VERSION 5.7 ;
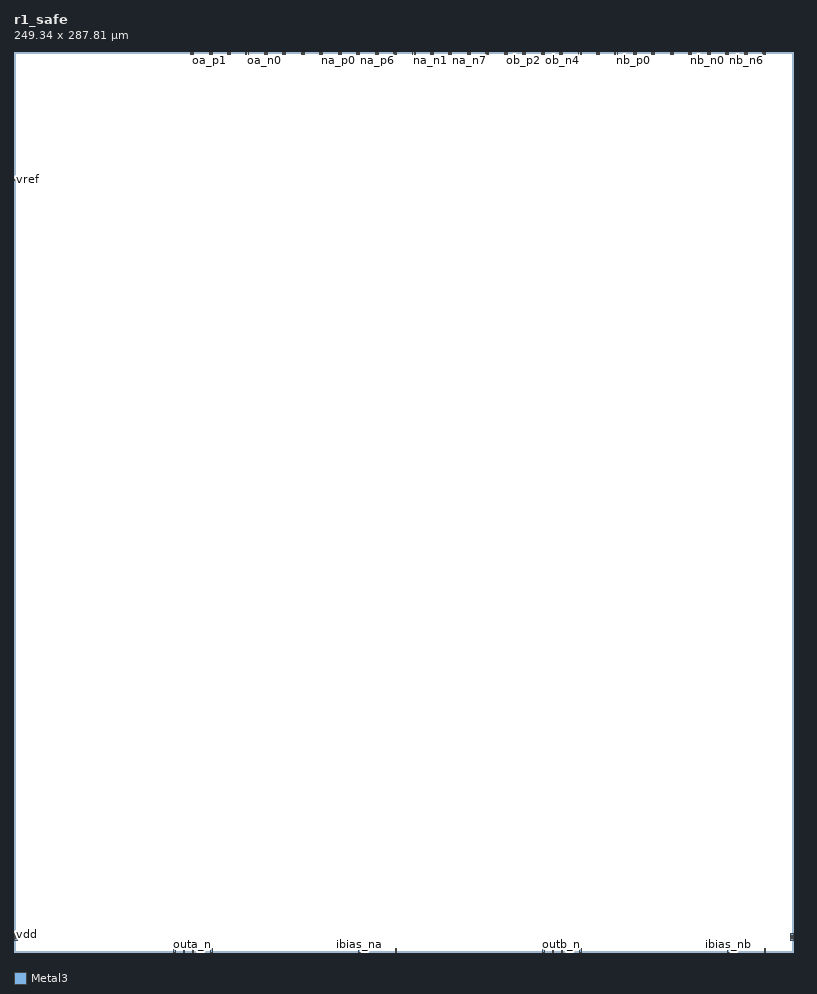
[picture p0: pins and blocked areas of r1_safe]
MACRO r1_safe
  CLASS BLOCK ;
  ORIGIN 0 0 ;
  SIZE 249.340 BY 287.810 ;
  PIN vref
    DIRECTION INOUT ;
    PORT
      LAYER Metal3 ;
        RECT 0.000 246.830 1.000 247.070 ;
    END
  END vref
  PIN vss
    DIRECTION INOUT ; USE GROUND ;
    PORT
      LAYER Metal3 ;
        RECT 0.000 3.800 1.000 4.200 ;
      LAYER Metal3 ;
        RECT 248.340 3.800 249.340 4.200 ;
    END
  END vss
  PIN vdda
    DIRECTION INOUT ; USE POWER ;
    PORT
      LAYER Metal3 ;
        RECT 0.000 4.600 1.000 5.000 ;
      LAYER Metal3 ;
        RECT 248.340 4.600 249.340 5.000 ;
    END
  END vdda
  PIN vdd
    DIRECTION INOUT ; USE POWER ;
    PORT
      LAYER Metal3 ;
        RECT 0.000 5.400 1.000 5.800 ;
      LAYER Metal3 ;
        RECT 248.340 5.400 249.340 5.800 ;
    END
  END vdd
  PIN oa_p0
    DIRECTION INOUT ;
    PORT
      LAYER Metal3 ;
        RECT 56.480 286.860 56.780 287.810 ;
    END
  END oa_p0
  PIN oa_p1
    DIRECTION INOUT ;
    PORT
      LAYER Metal3 ;
        RECT 62.380 286.860 62.680 287.810 ;
    END
  END oa_p1
  PIN oa_p2
    DIRECTION INOUT ;
    PORT
      LAYER Metal3 ;
        RECT 68.280 286.860 68.580 287.810 ;
    END
  END oa_p2
  PIN oa_p3
    DIRECTION INOUT ;
    PORT
      LAYER Metal3 ;
        RECT 74.180 286.860 74.480 287.810 ;
    END
  END oa_p3
  PIN oa_p4
    DIRECTION INOUT ;
    PORT
      LAYER Metal3 ;
        RECT 57.145 286.860 57.445 287.810 ;
    END
  END oa_p4
  PIN oa_p5
    DIRECTION INOUT ;
    PORT
      LAYER Metal3 ;
        RECT 63.045 286.860 63.345 287.810 ;
    END
  END oa_p5
  PIN oa_p6
    DIRECTION INOUT ;
    PORT
      LAYER Metal3 ;
        RECT 68.945 286.860 69.245 287.810 ;
    END
  END oa_p6
  PIN oa_p7
    DIRECTION INOUT ;
    PORT
      LAYER Metal3 ;
        RECT 74.845 286.860 75.145 287.810 ;
    END
  END oa_p7
  PIN oa_n0
    DIRECTION INOUT ;
    PORT
      LAYER Metal3 ;
        RECT 80.080 286.860 80.380 287.810 ;
    END
  END oa_n0
  PIN oa_n1
    DIRECTION INOUT ;
    PORT
      LAYER Metal3 ;
        RECT 85.980 286.860 86.280 287.810 ;
    END
  END oa_n1
  PIN oa_n2
    DIRECTION INOUT ;
    PORT
      LAYER Metal3 ;
        RECT 91.880 286.860 92.180 287.810 ;
    END
  END oa_n2
  PIN oa_n3
    DIRECTION INOUT ;
    PORT
      LAYER Metal3 ;
        RECT 97.780 286.860 98.080 287.810 ;
    END
  END oa_n3
  PIN oa_n4
    DIRECTION INOUT ;
    PORT
      LAYER Metal3 ;
        RECT 80.745 286.860 81.045 287.810 ;
    END
  END oa_n4
  PIN oa_n5
    DIRECTION INOUT ;
    PORT
      LAYER Metal3 ;
        RECT 86.645 286.860 86.945 287.810 ;
    END
  END oa_n5
  PIN oa_n6
    DIRECTION INOUT ;
    PORT
      LAYER Metal3 ;
        RECT 92.545 286.860 92.845 287.810 ;
    END
  END oa_n6
  PIN oa_n7
    DIRECTION INOUT ;
    PORT
      LAYER Metal3 ;
        RECT 98.445 286.860 98.745 287.810 ;
    END
  END oa_n7
  PIN na_p0
    DIRECTION INOUT ;
    PORT
      LAYER Metal3 ;
        RECT 103.680 286.860 103.980 287.810 ;
    END
  END na_p0
  PIN na_p1
    DIRECTION INOUT ;
    PORT
      LAYER Metal3 ;
        RECT 109.580 286.860 109.880 287.810 ;
    END
  END na_p1
  PIN na_p2
    DIRECTION INOUT ;
    PORT
      LAYER Metal3 ;
        RECT 115.480 286.860 115.780 287.810 ;
    END
  END na_p2
  PIN na_p3
    DIRECTION INOUT ;
    PORT
      LAYER Metal3 ;
        RECT 121.380 286.860 121.680 287.810 ;
    END
  END na_p3
  PIN na_p4
    DIRECTION INOUT ;
    PORT
      LAYER Metal3 ;
        RECT 104.345 286.860 104.645 287.810 ;
    END
  END na_p4
  PIN na_p5
    DIRECTION INOUT ;
    PORT
      LAYER Metal3 ;
        RECT 110.245 286.860 110.545 287.810 ;
    END
  END na_p5
  PIN na_p6
    DIRECTION INOUT ;
    PORT
      LAYER Metal3 ;
        RECT 116.145 286.860 116.445 287.810 ;
    END
  END na_p6
  PIN na_p7
    DIRECTION INOUT ;
    PORT
      LAYER Metal3 ;
        RECT 122.045 286.860 122.345 287.810 ;
    END
  END na_p7
  PIN na_n0
    DIRECTION INOUT ;
    PORT
      LAYER Metal3 ;
        RECT 127.280 286.860 127.580 287.810 ;
    END
  END na_n0
  PIN na_n1
    DIRECTION INOUT ;
    PORT
      LAYER Metal3 ;
        RECT 133.180 286.860 133.480 287.810 ;
    END
  END na_n1
  PIN na_n2
    DIRECTION INOUT ;
    PORT
      LAYER Metal3 ;
        RECT 139.080 286.860 139.380 287.810 ;
    END
  END na_n2
  PIN na_n3
    DIRECTION INOUT ;
    PORT
      LAYER Metal3 ;
        RECT 144.980 286.860 145.280 287.810 ;
    END
  END na_n3
  PIN na_n4
    DIRECTION INOUT ;
    PORT
      LAYER Metal3 ;
        RECT 127.945 286.860 128.245 287.810 ;
    END
  END na_n4
  PIN na_n5
    DIRECTION INOUT ;
    PORT
      LAYER Metal3 ;
        RECT 133.845 286.860 134.145 287.810 ;
    END
  END na_n5
  PIN na_n6
    DIRECTION INOUT ;
    PORT
      LAYER Metal3 ;
        RECT 139.745 286.860 140.045 287.810 ;
    END
  END na_n6
  PIN na_n7
    DIRECTION INOUT ;
    PORT
      LAYER Metal3 ;
        RECT 145.645 286.860 145.945 287.810 ;
    END
  END na_n7
  PIN ob_p0
    DIRECTION INOUT ;
    PORT
      LAYER Metal3 ;
        RECT 150.880 286.860 151.180 287.810 ;
    END
  END ob_p0
  PIN ob_p1
    DIRECTION INOUT ;
    PORT
      LAYER Metal3 ;
        RECT 156.780 286.860 157.080 287.810 ;
    END
  END ob_p1
  PIN ob_p2
    DIRECTION INOUT ;
    PORT
      LAYER Metal3 ;
        RECT 162.680 286.860 162.980 287.810 ;
    END
  END ob_p2
  PIN ob_p3
    DIRECTION INOUT ;
    PORT
      LAYER Metal3 ;
        RECT 168.580 286.860 168.880 287.810 ;
    END
  END ob_p3
  PIN ob_p4
    DIRECTION INOUT ;
    PORT
      LAYER Metal3 ;
        RECT 151.545 286.860 151.845 287.810 ;
    END
  END ob_p4
  PIN ob_p5
    DIRECTION INOUT ;
    PORT
      LAYER Metal3 ;
        RECT 157.445 286.860 157.745 287.810 ;
    END
  END ob_p5
  PIN ob_p6
    DIRECTION INOUT ;
    PORT
      LAYER Metal3 ;
        RECT 163.345 286.860 163.645 287.810 ;
    END
  END ob_p6
  PIN ob_p7
    DIRECTION INOUT ;
    PORT
      LAYER Metal3 ;
        RECT 169.245 286.860 169.545 287.810 ;
    END
  END ob_p7
  PIN ob_n0
    DIRECTION INOUT ;
    PORT
      LAYER Metal3 ;
        RECT 174.480 286.860 174.780 287.810 ;
    END
  END ob_n0
  PIN ob_n1
    DIRECTION INOUT ;
    PORT
      LAYER Metal3 ;
        RECT 180.380 286.860 180.680 287.810 ;
    END
  END ob_n1
  PIN ob_n2
    DIRECTION INOUT ;
    PORT
      LAYER Metal3 ;
        RECT 186.280 286.860 186.580 287.810 ;
    END
  END ob_n2
  PIN ob_n3
    DIRECTION INOUT ;
    PORT
      LAYER Metal3 ;
        RECT 192.180 286.860 192.480 287.810 ;
    END
  END ob_n3
  PIN ob_n4
    DIRECTION INOUT ;
    PORT
      LAYER Metal3 ;
        RECT 175.145 286.860 175.445 287.810 ;
    END
  END ob_n4
  PIN ob_n5
    DIRECTION INOUT ;
    PORT
      LAYER Metal3 ;
        RECT 181.045 286.860 181.345 287.810 ;
    END
  END ob_n5
  PIN ob_n6
    DIRECTION INOUT ;
    PORT
      LAYER Metal3 ;
        RECT 186.945 286.860 187.245 287.810 ;
    END
  END ob_n6
  PIN ob_n7
    DIRECTION INOUT ;
    PORT
      LAYER Metal3 ;
        RECT 192.845 286.860 193.145 287.810 ;
    END
  END ob_n7
  PIN nb_p0
    DIRECTION INOUT ;
    PORT
      LAYER Metal3 ;
        RECT 198.080 286.860 198.380 287.810 ;
    END
  END nb_p0
  PIN nb_p1
    DIRECTION INOUT ;
    PORT
      LAYER Metal3 ;
        RECT 203.980 286.860 204.280 287.810 ;
    END
  END nb_p1
  PIN nb_p2
    DIRECTION INOUT ;
    PORT
      LAYER Metal3 ;
        RECT 209.880 286.860 210.180 287.810 ;
    END
  END nb_p2
  PIN nb_p3
    DIRECTION INOUT ;
    PORT
      LAYER Metal3 ;
        RECT 215.780 286.860 216.080 287.810 ;
    END
  END nb_p3
  PIN nb_p4
    DIRECTION INOUT ;
    PORT
      LAYER Metal3 ;
        RECT 198.745 286.860 199.045 287.810 ;
    END
  END nb_p4
  PIN nb_p5
    DIRECTION INOUT ;
    PORT
      LAYER Metal3 ;
        RECT 204.645 286.860 204.945 287.810 ;
    END
  END nb_p5
  PIN nb_p6
    DIRECTION INOUT ;
    PORT
      LAYER Metal3 ;
        RECT 210.545 286.860 210.845 287.810 ;
    END
  END nb_p6
  PIN nb_p7
    DIRECTION INOUT ;
    PORT
      LAYER Metal3 ;
        RECT 216.445 286.860 216.745 287.810 ;
    END
  END nb_p7
  PIN nb_n0
    DIRECTION INOUT ;
    PORT
      LAYER Metal3 ;
        RECT 221.680 286.860 221.980 287.810 ;
    END
  END nb_n0
  PIN nb_n1
    DIRECTION INOUT ;
    PORT
      LAYER Metal3 ;
        RECT 227.580 286.860 227.880 287.810 ;
    END
  END nb_n1
  PIN nb_n2
    DIRECTION INOUT ;
    PORT
      LAYER Metal3 ;
        RECT 233.480 286.860 233.780 287.810 ;
    END
  END nb_n2
  PIN nb_n3
    DIRECTION INOUT ;
    PORT
      LAYER Metal3 ;
        RECT 239.380 286.860 239.680 287.810 ;
    END
  END nb_n3
  PIN nb_n4
    DIRECTION INOUT ;
    PORT
      LAYER Metal3 ;
        RECT 222.345 286.860 222.645 287.810 ;
    END
  END nb_n4
  PIN nb_n5
    DIRECTION INOUT ;
    PORT
      LAYER Metal3 ;
        RECT 228.245 286.860 228.545 287.810 ;
    END
  END nb_n5
  PIN nb_n6
    DIRECTION INOUT ;
    PORT
      LAYER Metal3 ;
        RECT 234.145 286.860 234.445 287.810 ;
    END
  END nb_n6
  PIN nb_n7
    DIRECTION INOUT ;
    PORT
      LAYER Metal3 ;
        RECT 240.045 286.860 240.345 287.810 ;
    END
  END nb_n7
  PIN oc_a
    DIRECTION INOUT ;
    PORT
      LAYER Metal3 ;
        RECT 62.870 0.000 63.470 1.000 ;
    END
  END oc_a
  PIN ibias_oa
    DIRECTION INOUT ;
    PORT
      LAYER Metal3 ;
        RECT 51.120 0.000 51.720 1.000 ;
    END
  END ibias_oa
  PIN neg_a
    DIRECTION INOUT ;
    PORT
      LAYER Metal3 ;
        RECT 121.870 0.000 122.470 1.000 ;
    END
  END neg_a
  PIN ibias_na
    DIRECTION INOUT ;
    PORT
      LAYER Metal3 ;
        RECT 110.120 0.000 110.720 1.000 ;
    END
  END ibias_na
  PIN oc_b
    DIRECTION INOUT ;
    PORT
      LAYER Metal3 ;
        RECT 180.870 0.000 181.470 1.000 ;
    END
  END oc_b
  PIN ibias_ob
    DIRECTION INOUT ;
    PORT
      LAYER Metal3 ;
        RECT 169.120 0.000 169.720 1.000 ;
    END
  END ibias_ob
  PIN neg_b
    DIRECTION INOUT ;
    PORT
      LAYER Metal3 ;
        RECT 239.870 0.000 240.470 1.000 ;
    END
  END neg_b
  PIN ibias_nb
    DIRECTION INOUT ;
    PORT
      LAYER Metal3 ;
        RECT 228.120 0.000 228.720 1.000 ;
    END
  END ibias_nb
  PIN outa_p
    DIRECTION INOUT ;
    PORT
      LAYER Metal3 ;
        RECT 54.160 0.000 54.460 1.000 ;
    END
  END outa_p
  PIN outa_n
    DIRECTION INOUT ;
    PORT
      LAYER Metal3 ;
        RECT 57.080 0.000 57.380 1.000 ;
    END
  END outa_n
  PIN outb_p
    DIRECTION INOUT ;
    PORT
      LAYER Metal3 ;
        RECT 172.160 0.000 172.460 1.000 ;
    END
  END outb_p
  PIN outb_n
    DIRECTION INOUT ;
    PORT
      LAYER Metal3 ;
        RECT 175.080 0.000 175.380 1.000 ;
    END
  END outb_n
END r1_safe
END LIBRARY
